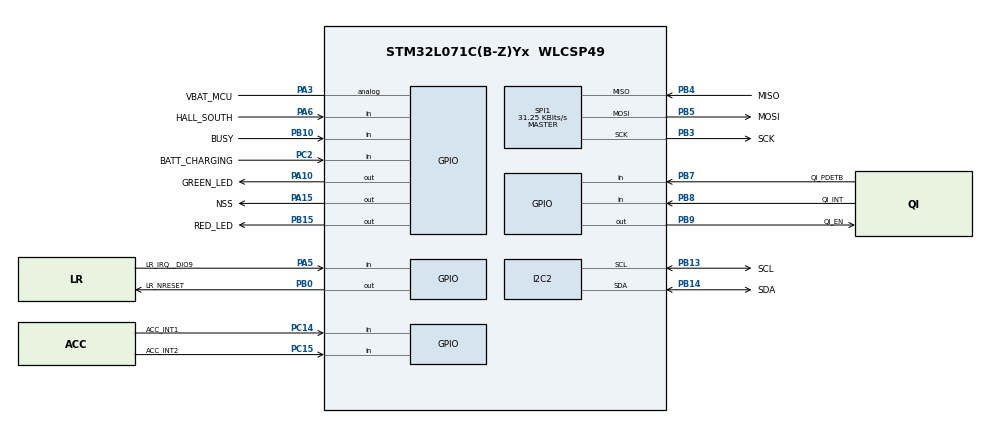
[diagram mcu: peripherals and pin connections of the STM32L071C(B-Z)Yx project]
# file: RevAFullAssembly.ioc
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I2C2.Timing=0x00000000
Mcu.Family=STM32L0
Mcu.Name=STM32L071C(B-Z)Yx
Mcu.Package=WLCSP49
PA10.GPIO_Label=GREEN_LED
PA10.GPIO_ModeDefaultOutputPP=GPIO_MODE_OUTPUT_OD
PA10.PinState=GPIO_PIN_SET
PA10.Signal=GPIO_Output
PA13.GPIO_Label=SWDIO
PA13.Mode=Serial_Wire
PA13.Signal=SYS_SWDIO
PA14.GPIO_Label=SWCLK
PA14.Mode=Serial_Wire
PA14.Signal=SYS_SWCLK
PA15.GPIO_Label=NSS
PA15.GPIO_Speed=GPIO_SPEED_FREQ_VERY_HIGH
PA15.PinState=GPIO_PIN_SET
PA15.Signal=GPIO_Output
PA3.GPIO_Label=VBAT_MCU
PA3.Signal=GPIO_Analog
PA5.GPIO_Label=LR_IRQ__DIO9
PA5.Signal=GPIO_Input
PA6.GPIO_Label=HALL_SOUTH
PA6.GPIO_PuPd=GPIO_PULLUP
PA6.Signal=GPIO_Input
PB0.GPIO_Label=LR_NRESET
PB0.GPIO_ModeDefaultOutputPP=GPIO_MODE_OUTPUT_PP
PB0.GPIO_Speed=GPIO_SPEED_FREQ_VERY_HIGH
PB0.PinState=GPIO_PIN_SET
PB0.Signal=GPIO_Output
PB10.GPIO_Label=BUSY
PB10.Signal=GPIO_Input
PB13.GPIO_Label=SCL
PB13.Mode=I2C
PB13.Signal=I2C2_SCL
PB14.GPIO_Label=SDA
PB14.Mode=I2C
PB14.Signal=I2C2_SDA
PB15.GPIO_Label=RED_LED
PB15.GPIO_ModeDefaultOutputPP=GPIO_MODE_OUTPUT_OD
PB15.PinState=GPIO_PIN_SET
PB15.Signal=GPIO_Output
PB3.GPIO_Label=SCK
PB3.GPIO_Speed=GPIO_SPEED_FREQ_VERY_HIGH
PB3.Mode=Full_Duplex_Master
PB3.Signal=SPI1_SCK
PB4.GPIO_Label=MISO
PB4.GPIO_Speed=GPIO_SPEED_FREQ_VERY_HIGH
PB4.Mode=Full_Duplex_Master
PB4.Signal=SPI1_MISO
PB5.GPIO_Label=MOSI
PB5.GPIO_Speed=GPIO_SPEED_FREQ_VERY_HIGH
PB5.Mode=Full_Duplex_Master
PB5.Signal=SPI1_MOSI
PB7.GPIO_Label=QI_PDETB
PB7.GPIO_PuPd=GPIO_PULLUP
PB7.Signal=GPIO_Input
PB8.GPIO_Label=QI_INT
PB8.GPIO_PuPd=GPIO_PULLUP
PB8.Signal=GPIO_Input
PB9.GPIO_Label=QI_EN
PB9.GPIO_PuPd=GPIO_PULLDOWN
PB9.Signal=GPIO_Output
PC14-OSC32_IN.GPIO_Label=ACC_INT1
PC14-OSC32_IN.Signal=GPIO_Input
PC15-OSC32_OUT.GPIO_Label=ACC_INT2
PC15-OSC32_OUT.Signal=GPIO_Input
PC2.GPIO_Label=BATT_CHARGING
PC2.GPIO_PuPd=GPIO_PULLUP
PC2.Signal=GPIO_Input
ProjectManager.HeapSize=0x200
ProjectManager.StackSize=0x400
ProjectManager.TargetToolchain=STM32CubeIDE
RCC.ADCFreq_Value=4000000
RCC.AHBCLKDivider=RCC_SYSCLK_DIV16
RCC.AHBFreq_Value=250000
RCC.APB1Freq_Value=250000
RCC.APB1TimFreq_Value=250000
RCC.APB2Freq_Value=250000
RCC.APB2TimFreq_Value=250000
RCC.HCLKFreq_Value=250000
RCC.HSE_VALUE=8000000
RCC.HSI16_VALUE=16000000
RCC.HSIRCDiv=4
RCC.HSI_VALUE=4000000
RCC.LSE_VALUE=32768
RCC.MSIClockRange=RCC_MSIRANGE_0
RCC.MSI_VALUE=65536
RCC.PLLDIV=RCC_PLLDIV_4
RCC.PLLMUL=RCC_PLLMUL_4
RCC.SYSCLKFreq_VALUE=4000000
RCC.SYSCLKSource=RCC_SYSCLKSOURCE_PLLCLK
RCC.VCOOutputFreq_Value=16000000
SPI1.BaudRatePrescaler=SPI_BAUDRATEPRESCALER_8
SPI1.CalculateBaudRate=31.25 KBits/s
SPI1.Direction=SPI_DIRECTION_2LINES
SPI1.Mode=SPI_MODE_MASTER
SPI1.VirtualType=VM_MASTER
board=custom

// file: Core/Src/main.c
/* USER CODE BEGIN Header */
/**
  ******************************************************************************
  * @file           : main.c
  * @brief          : Main program body
  ******************************************************************************
  * @attention
  *
  * <h2><center>&copy; Copyright (c) 2021 STMicroelectronics.
  * All rights reserved.</center></h2>
  *
  * This software component is licensed by ST under BSD 3-Clause license,
  * the "License"; You may not use this file except in compliance with the
  * License. You may obtain a copy of the License at:
  *                        opensource.org/licenses/BSD-3-Clause
  *
  ******************************************************************************
  */
/* USER CODE END Header */
#include "main.h"

/* USER CODE BEGIN Includes */

// Switch includes based on the step to run
// STEP 1
#include "lr1110_modem_1.0.7_part-1.h"
// #include "lr_1110_transceiver_304_part-1.h"

// STEP 2
#include "lr1110_modem_1.0.7_part-2.h"
// #include "lr_1110_transceiver_304_part-2.h"

#include "configuration.h"
#include "lr1110_bootloader.h"
#include "lr1110_system.h"
#include "lr1110_system_types.h"
#include "system.h"

#include "lr1110_wifi.h"
#include "lr1110_wifi_types.h"
#include "lr1110_gnss.h"
#include "lr1110_gnss_types.h"

#include "lr1110_modem_system.h"
#include "lr1110_modem_lorawan.h"

/* USER CODE END Includes */

I2C_HandleTypeDef hi2c2;

SPI_HandleTypeDef hspi1;

void SystemClock_Config(void);
static void MX_GPIO_Init(void);
static void MX_I2C2_Init(void);
static void MX_SPI1_Init(void);

int main(void)
{

  /* MCU Configuration--------------------------------------------------------*/

  /* Reset of all peripherals, Initializes the Flash interface and the Systick. */
  HAL_Init();

  /* Configure the system clock */
  SystemClock_Config();

  /* Initialize all configured peripherals */
  MX_GPIO_Init();
  MX_I2C2_Init();
  MX_SPI1_Init();
  /* USER CODE BEGIN 2 */

  radio_t radio = {
	&hspi1,
	{ NSS_GPIO_Port, NSS_Pin },
	{ LR_NRESET_GPIO_Port, LR_NRESET_Pin },
    { LR_IRQ__DIO9_GPIO_Port, LR_IRQ__DIO9_Pin },
    { BUSY_GPIO_Port, BUSY_Pin },
  };

  lr1110_bootloader_version_t version_system = { 0 };
  lr1110_modem_version_t modem_version = { 0 };

  //  lr1110_modem_status_t modem_status = { 0 };
//  lr1110_modem_response_code_t modem_return;
//  lr1110_modem_event_fields_t modem_event;

  lr1110_system_stat1_t lr_stat1;
  lr1110_system_stat2_t lr_stat2;
  lr1110_system_irq_mask_t lr_irq_status;
  lr1110_system_errors_t lr_errors;

  lr1110_status_t lr_status = LR1110_STATUS_ERROR;

  // lr1110_modem_chip_eui_t chip_eui;

/*
  lr1110_hal_reset( &radio );
  lr1110_bootloader_reboot(&radio, false);
  HAL_Delay(2500);
  lr1110_bootloader_get_version(&radio, &version_system);
  lr1110_modem_get_version( &radio, &modem_version );
  modem_return = lr1110_modem_suspend( &radio, LR1110_MODEM_RESUMED);
  modem_return = lr1110_modem_get_status( &radio, &modem_status );
  modem_return = lr1110_modem_get_chip_eui( &radio, &chip_eui );
  lr1110_modem_system_reboot( &radio, false );
  lr1110_bootloader_get_version(&radio, &version_system);
  lr1110_modem_get_version( &radio, &modem_version );
*/

  /* START GNSS test */
  /*
  lr1110_hal_reset( &radio );
  HAL_GPIO_TogglePin(GREEN_LED_GPIO_Port, GREEN_LED_Pin);
  HAL_Delay(500);
  HAL_GPIO_TogglePin(GREEN_LED_GPIO_Port, GREEN_LED_Pin);
  // lr1110_modem_get_version(&radio, &modem_version);
  lr1110_bootloader_get_version(&radio, &version_system);
  lr_status = lr1110_system_get_version(&radio, &version);

  lr_status = lr1110_system_get_status(&radio, &lr_stat1, &lr_stat2, &lr_irq_status);
  lr_status = lr1110_system_get_errors(&radio, &lr_errors);

  lr_status = lr1110_system_set_reg_mode(&radio, LR1110_SYSTEM_REG_MODE_DCDC);

  lr1110_system_rfswitch_cfg_t rf_switch_setup = { 0 };
  rf_switch_setup.enable                       = LR1110_SYSTEM_RFSW2_HIGH;
  rf_switch_setup.standby                      = 0xFF;
  rf_switch_setup.tx                           = 0x00;
  rf_switch_setup.tx_hp                        = 0x00;
  rf_switch_setup.rx                           = 0x00;
  rf_switch_setup.wifi                         = 0x00;
  rf_switch_setup.gnss                         = LR1110_SYSTEM_RFSW2_HIGH;

  lr_status = lr1110_system_set_dio_as_rf_switch(&radio, &rf_switch_setup);

  lr_status = lr1110_system_cfg_lfclk(&radio, LR1110_SYSTEM_LFCLK_XTAL, true);
  lr_status = lr1110_system_set_tcxo_mode(&radio, LR1110_SYSTEM_TCXO_CTRL_1_8V, 500);
  lr_status = lr1110_system_calibrate(&radio, 0x3F);

  uint32_t local_time = 1614157841;
  uint16_t gnss_result_size = 0;
  uint8_t gnss_results[LR1110_GNSS_MAX_SIZE_ARRAY] = { 0 };
  uint8_t nb_sv_detected = 0;
  lr1110_gnss_detected_satellite_t list_of_sv[32] = { 0 };

  lr_status = lr1110_gnss_set_constellations_to_use(&radio, LR1110_GNSS_GPS_MASK + LR1110_GNSS_BEIDOU_MASK);

  while (!nb_sv_detected)
  {
	  HAL_GPIO_TogglePin(RED_LED_GPIO_Port, RED_LED_Pin);
	  lr_status = lr1110_gnss_scan_autonomous(&radio, local_time, LR1110_GNSS_OPTION_BEST_EFFORT, LR1110_GNSS_BIT_CHANGE_MASK | LR1110_GNSS_DOPPLER_MASK | LR1110_GNSS_IRQ_PSEUDO_RANGE_MASK, 0);
	  lr_status = lr1110_gnss_get_result_size(&radio, &gnss_result_size);
	  lr_status = lr1110_gnss_read_results(&radio, gnss_results, gnss_result_size);
	  lr_status = lr1110_gnss_get_nb_detected_satellites(&radio, &nb_sv_detected );
	  lr_status = lr1110_gnss_get_detected_satellites(&radio, nb_sv_detected, list_of_sv);

	  HAL_GPIO_TogglePin(RED_LED_GPIO_Port, RED_LED_Pin);
	  HAL_Delay(5000);
  }

  int i;

  for (i = 0; i < nb_sv_detected; ++i)
  {
	  HAL_GPIO_TogglePin(GREEN_LED_GPIO_Port, GREEN_LED_Pin);
	  HAL_Delay(500);
	  HAL_GPIO_TogglePin(GREEN_LED_GPIO_Port, GREEN_LED_Pin);
  }

  HAL_Delay(5000);
  */

  /* END GNSS test */

  /*
  // lr1110_wifi_channel_mask_t channels = LR1110_WIFI_CHANNEL_1_MASK + LR1110_WIFI_CHANNEL_2_MASK + LR1110_WIFI_CHANNEL_3_MASK + LR1110_WIFI_CHANNEL_4_MASK + LR1110_WIFI_CHANNEL_5_MASK + LR1110_WIFI_CHANNEL_6_MASK;
  lr1110_wifi_channel_mask_t channels = 0b0011111111111111;
  lr_status = lr1110_wifi_scan(&radio, LR1110_WIFI_TYPE_SCAN_B_G_N, channels, LR1110_WIFI_SCAN_MODE_FULL_BEACON, 16, 4, 110, false);

  lr_status = lr1110_system_get_errors(&radio, &lr_errors);

  uint8_t nb_results = 0;
  lr1110_wifi_get_nb_results(&radio, &nb_results);
  lr1110_wifi_extended_full_result_t all_results[LR1110_WIFI_MAX_RESULTS] = {0};
  lr1110_wifi_read_extended_full_results(&radio, 0, nb_results, all_results);
  */

  // lr1110_hal_wakeup( &radio );
//  HAL_GPIO_TogglePin(RED_LED_GPIO_Port, RED_LED_Pin);
//  HAL_Delay(500);
//  HAL_GPIO_TogglePin(RED_LED_GPIO_Port, RED_LED_Pin);
//  HAL_GPIO_TogglePin(GREEN_LED_GPIO_Port, GREEN_LED_Pin);
//  HAL_Delay(500);
//  HAL_GPIO_TogglePin(GREEN_LED_GPIO_Port, GREEN_LED_Pin);

  // lr1110_system_set_tcxo_mode(&radio, LR1110_SYSTEM_TCXO_CTRL_1_6V, 10000);

  // lr1110_hal_bootstrap( &radio );

  /* START LR1110 Firmware Update */
  // Rebooting into bootstrap
  lr1110_hal_bootstrap( &radio );
  lr1110_hal_reset( &radio );
  HAL_Delay(500);
  lr1110_bootloader_get_version(&radio, &version_system);

  if( version_system.type != 0xDF )
  {
	lr1110_bootloader_reboot( &radio, true );
	HAL_Delay(500);
  }

  /*
  lr1110_bootloader_get_version(&radio, &version_system);
  lr1110_hal_bootstrap(&radio);
  lr1110_bootloader_get_version(&radio, &version_system);
  lr1110_modem_get_version(&radio, &modem);
  */

  // STEP 1
  lr1110_bootloader_erase_flash( &radio );
  lr1110_bootloader_get_version(&radio, &version_system);

  lr_status = lr1110_bootloader_write_flash_encrypted_full( &radio, 0, lr1110_firmware_image, ( uint32_t ) LR1110_FIRMWARE_IMAGE_SIZE );
  lr1110_hal_reset( &radio );
  lr1110_bootloader_get_version(&radio, &version_system);

  // STEP 2 - offset is taken from STEP 1
  lr_status = lr1110_bootloader_write_flash_encrypted_full( &radio, 163328, lr1110_firmware_image, ( uint32_t ) LR1110_FIRMWARE_IMAGE_SIZE );

  // Rebooting out of bootstrap
  lr1110_bootloader_reboot( &radio, false );
  lr1110_modem_system_reboot(&radio, false);
  HAL_Delay(2500);

  /*
  lr1110_hal_reset( &radio );
  lr1110_bootloader_reboot( &radio, false );
  lr1110_bootloader_get_version(&radio, &version_system);
  */
  lr1110_modem_get_version(&radio, &modem_version);

  // lr1110_bootloader_read_pin( &radio, pin );
  // lr1110_bootloader_read_chip_eui( &radio, chip_eui );
  // lr1110_bootloader_read_join_eui( &radio, join_eui );
  /**/

  // lr1110_system_get_temp(&radio, &lr_temp);

  /* USER CODE END 2 */

  /* Infinite loop */
  /* USER CODE BEGIN WHILE */
  while (1)
  {
    HAL_GPIO_TogglePin(RED_LED_GPIO_Port, RED_LED_Pin);
    HAL_Delay(500);
    HAL_GPIO_TogglePin(RED_LED_GPIO_Port, RED_LED_Pin);
    HAL_GPIO_TogglePin(GREEN_LED_GPIO_Port, GREEN_LED_Pin);
    HAL_Delay(500);
    HAL_GPIO_TogglePin(GREEN_LED_GPIO_Port, GREEN_LED_Pin);
    /* USER CODE END WHILE */

  }
}

void SystemClock_Config(void)
{
  RCC_OscInitTypeDef RCC_OscInitStruct = {0};
  RCC_ClkInitTypeDef RCC_ClkInitStruct = {0};

  /** Configure the main internal regulator output voltage
  */
  __HAL_PWR_VOLTAGESCALING_CONFIG(PWR_REGULATOR_VOLTAGE_SCALE1);
  /** Initializes the RCC Oscillators according to the specified parameters
  * in the RCC_OscInitTypeDef structure.
  */
  RCC_OscInitStruct.OscillatorType = RCC_OSCILLATORTYPE_HSI;
  RCC_OscInitStruct.HSIState = RCC_HSI_ON;
  RCC_OscInitStruct.HSICalibrationValue = RCC_HSICALIBRATION_DEFAULT;
  RCC_OscInitStruct.PLL.PLLState = RCC_PLL_ON;
  RCC_OscInitStruct.PLL.PLLSource = RCC_PLLSOURCE_HSI;
  RCC_OscInitStruct.PLL.PLLMUL = RCC_PLLMUL_4;
  RCC_OscInitStruct.PLL.PLLDIV = RCC_PLLDIV_4;
  if (HAL_RCC_OscConfig(&RCC_OscInitStruct) != HAL_OK)
  {
    Error_Handler();
  }
  /** Initializes the CPU, AHB and APB buses clocks
  */
  RCC_ClkInitStruct.ClockType = RCC_CLOCKTYPE_HCLK|RCC_CLOCKTYPE_SYSCLK
                              |RCC_CLOCKTYPE_PCLK1|RCC_CLOCKTYPE_PCLK2;
  RCC_ClkInitStruct.SYSCLKSource = RCC_SYSCLKSOURCE_PLLCLK;
  RCC_ClkInitStruct.AHBCLKDivider = RCC_SYSCLK_DIV2;
  RCC_ClkInitStruct.APB1CLKDivider = RCC_HCLK_DIV1;
  RCC_ClkInitStruct.APB2CLKDivider = RCC_HCLK_DIV1;

  if (HAL_RCC_ClockConfig(&RCC_ClkInitStruct, FLASH_LATENCY_0) != HAL_OK)
  {
    Error_Handler();
  }
}

static void MX_I2C2_Init(void)
{

  hi2c2.Instance = I2C2;
  hi2c2.Init.Timing = 0x2000090E;
  hi2c2.Init.OwnAddress1 = 0;
  hi2c2.Init.AddressingMode = I2C_ADDRESSINGMODE_7BIT;
  hi2c2.Init.DualAddressMode = I2C_DUALADDRESS_DISABLE;
  hi2c2.Init.OwnAddress2 = 0;
  hi2c2.Init.OwnAddress2Masks = I2C_OA2_NOMASK;
  hi2c2.Init.GeneralCallMode = I2C_GENERALCALL_DISABLE;
  hi2c2.Init.NoStretchMode = I2C_NOSTRETCH_DISABLE;
  if (HAL_I2C_Init(&hi2c2) != HAL_OK)
  {
    Error_Handler();
  }
  /** Configure Analogue filter
  */
  if (HAL_I2CEx_ConfigAnalogFilter(&hi2c2, I2C_ANALOGFILTER_ENABLE) != HAL_OK)
  {
    Error_Handler();
  }
  /** Configure Digital filter
  */
  if (HAL_I2CEx_ConfigDigitalFilter(&hi2c2, 0) != HAL_OK)
  {
    Error_Handler();
  }

}

static void MX_SPI1_Init(void)
{

  /* SPI1 parameter configuration*/
  hspi1.Instance = SPI1;
  hspi1.Init.Mode = SPI_MODE_MASTER;
  hspi1.Init.Direction = SPI_DIRECTION_2LINES;
  hspi1.Init.DataSize = SPI_DATASIZE_8BIT;
  hspi1.Init.CLKPolarity = SPI_POLARITY_LOW;
  hspi1.Init.CLKPhase = SPI_PHASE_1EDGE;
  hspi1.Init.NSS = SPI_NSS_SOFT;
  hspi1.Init.BaudRatePrescaler = SPI_BAUDRATEPRESCALER_8;
  hspi1.Init.FirstBit = SPI_FIRSTBIT_MSB;
  hspi1.Init.TIMode = SPI_TIMODE_DISABLE;
  hspi1.Init.CRCCalculation = SPI_CRCCALCULATION_DISABLE;
  hspi1.Init.CRCPolynomial = 7;
  if (HAL_SPI_Init(&hspi1) != HAL_OK)
  {
    Error_Handler();
  }

}

static void MX_GPIO_Init(void)
{
  GPIO_InitTypeDef GPIO_InitStruct = {0};

  /* GPIO Ports Clock Enable */
  __HAL_RCC_GPIOA_CLK_ENABLE();
  __HAL_RCC_GPIOB_CLK_ENABLE();
  __HAL_RCC_GPIOC_CLK_ENABLE();

  /*Configure GPIO pin Output Level */
  HAL_GPIO_WritePin(GPIOA, NSS_Pin|GREEN_LED_Pin, GPIO_PIN_SET);

  /*Configure GPIO pin Output Level */
  HAL_GPIO_WritePin(QI_EN_GPIO_Port, QI_EN_Pin, GPIO_PIN_RESET);

  /*Configure GPIO pin Output Level */
  HAL_GPIO_WritePin(GPIOB, RED_LED_Pin|LR_NRESET_Pin, GPIO_PIN_SET);

  /*Configure GPIO pin : NSS_Pin */
  GPIO_InitStruct.Pin = NSS_Pin;
  GPIO_InitStruct.Mode = GPIO_MODE_OUTPUT_PP;
  GPIO_InitStruct.Pull = GPIO_NOPULL;
  GPIO_InitStruct.Speed = GPIO_SPEED_FREQ_VERY_HIGH;
  HAL_GPIO_Init(NSS_GPIO_Port, &GPIO_InitStruct);

  /*Configure GPIO pin : QI_EN_Pin */
  GPIO_InitStruct.Pin = QI_EN_Pin;
  GPIO_InitStruct.Mode = GPIO_MODE_OUTPUT_PP;
  GPIO_InitStruct.Pull = GPIO_PULLDOWN;
  GPIO_InitStruct.Speed = GPIO_SPEED_FREQ_LOW;
  HAL_GPIO_Init(QI_EN_GPIO_Port, &GPIO_InitStruct);

  /*Configure GPIO pins : QI_INT_Pin QI_PDETB_Pin */
  GPIO_InitStruct.Pin = QI_INT_Pin|QI_PDETB_Pin;
  GPIO_InitStruct.Mode = GPIO_MODE_INPUT;
  GPIO_InitStruct.Pull = GPIO_PULLUP;
  HAL_GPIO_Init(GPIOB, &GPIO_InitStruct);

  /*Configure GPIO pin : GREEN_LED_Pin */
  GPIO_InitStruct.Pin = GREEN_LED_Pin;
  GPIO_InitStruct.Mode = GPIO_MODE_OUTPUT_OD;
  GPIO_InitStruct.Pull = GPIO_NOPULL;
  GPIO_InitStruct.Speed = GPIO_SPEED_FREQ_LOW;
  HAL_GPIO_Init(GREEN_LED_GPIO_Port, &GPIO_InitStruct);

  /*Configure GPIO pins : ACC_INT1_Pin ACC_INT2_Pin */
  GPIO_InitStruct.Pin = ACC_INT1_Pin|ACC_INT2_Pin;
  GPIO_InitStruct.Mode = GPIO_MODE_INPUT;
  GPIO_InitStruct.Pull = GPIO_NOPULL;
  HAL_GPIO_Init(GPIOC, &GPIO_InitStruct);

  /*Configure GPIO pin : RED_LED_Pin */
  GPIO_InitStruct.Pin = RED_LED_Pin;
  GPIO_InitStruct.Mode = GPIO_MODE_OUTPUT_OD;
  GPIO_InitStruct.Pull = GPIO_NOPULL;
  GPIO_InitStruct.Speed = GPIO_SPEED_FREQ_LOW;
  HAL_GPIO_Init(RED_LED_GPIO_Port, &GPIO_InitStruct);

  /*Configure GPIO pin : BATT_CHARGING_Pin */
  GPIO_InitStruct.Pin = BATT_CHARGING_Pin;
  GPIO_InitStruct.Mode = GPIO_MODE_INPUT;
  GPIO_InitStruct.Pull = GPIO_PULLUP;
  HAL_GPIO_Init(BATT_CHARGING_GPIO_Port, &GPIO_InitStruct);

  /*Configure GPIO pin : BUSY_Pin */
  GPIO_InitStruct.Pin = BUSY_Pin;
  GPIO_InitStruct.Mode = GPIO_MODE_INPUT;
  GPIO_InitStruct.Pull = GPIO_NOPULL;
  HAL_GPIO_Init(BUSY_GPIO_Port, &GPIO_InitStruct);

  /*Configure GPIO pin : LR_NRESET_Pin */
  GPIO_InitStruct.Pin = LR_NRESET_Pin;
  GPIO_InitStruct.Mode = GPIO_MODE_OUTPUT_PP;
  GPIO_InitStruct.Pull = GPIO_NOPULL;
  GPIO_InitStruct.Speed = GPIO_SPEED_FREQ_VERY_HIGH;
  HAL_GPIO_Init(LR_NRESET_GPIO_Port, &GPIO_InitStruct);

  /*Configure GPIO pin : HALL_SOUTH_Pin */
  GPIO_InitStruct.Pin = HALL_SOUTH_Pin;
  GPIO_InitStruct.Mode = GPIO_MODE_INPUT;
  GPIO_InitStruct.Pull = GPIO_PULLUP;
  HAL_GPIO_Init(HALL_SOUTH_GPIO_Port, &GPIO_InitStruct);

  /*Configure GPIO pin : LR_IRQ__DIO9_Pin */
  GPIO_InitStruct.Pin = LR_IRQ__DIO9_Pin;
  GPIO_InitStruct.Mode = GPIO_MODE_INPUT;
  GPIO_InitStruct.Pull = GPIO_NOPULL;
  HAL_GPIO_Init(LR_IRQ__DIO9_GPIO_Port, &GPIO_InitStruct);

  /*Configure GPIO pin : VBAT_MCU_Pin */
  GPIO_InitStruct.Pin = VBAT_MCU_Pin;
  GPIO_InitStruct.Mode = GPIO_MODE_ANALOG;
  GPIO_InitStruct.Pull = GPIO_NOPULL;
  HAL_GPIO_Init(VBAT_MCU_GPIO_Port, &GPIO_InitStruct);

}

void Error_Handler(void)
{
  __disable_irq();
  while (1)
  {
  }
}

/************************ (C) COPYRIGHT STMicroelectronics *****END OF FILE****/
